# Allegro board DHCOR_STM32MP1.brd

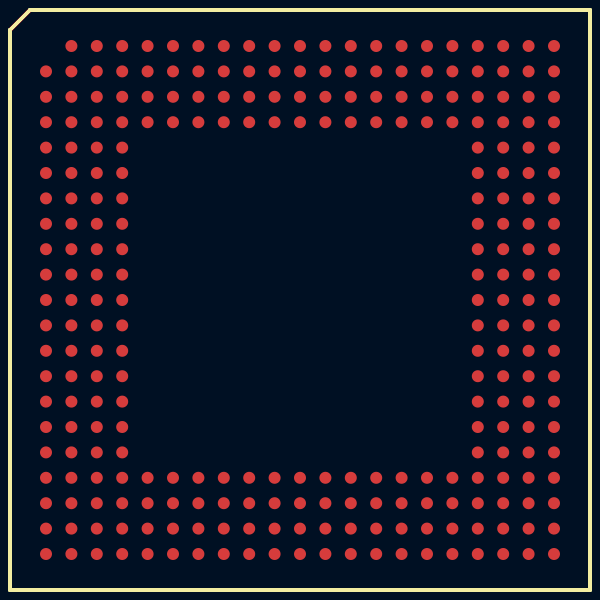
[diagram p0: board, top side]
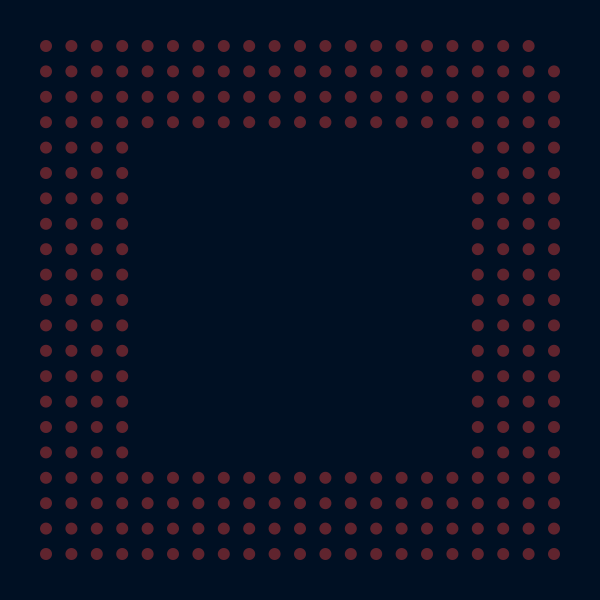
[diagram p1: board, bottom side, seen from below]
No outline. copper layers: TOP, BOTTOM. Coordinates in mm from the lowest, leftmost part position.

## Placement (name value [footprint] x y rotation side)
X?  -  [unnamed]  0 0 0 top

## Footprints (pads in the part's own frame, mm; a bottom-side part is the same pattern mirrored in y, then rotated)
unnamed
  round 0.6 smd: A2(-11.43,12.7) A3(-10.16,12.7) A4(-8.89,12.7) A5(-7.62,12.7) A6(-6.35,12.7) A7(-5.08,12.7) A8(-3.81,12.7) A9(-2.54,12.7) A10(-1.27,12.7) A11(0,12.7) A12(1.27,12.7) A13(2.54,12.7) A14(3.81,12.7) A15(5.08,12.7) A16(6.35,12.7) A17(7.62,12.7) A18(8.89,12.7) A19(10.16,12.7) A20(11.43,12.7) A21(12.7,12.7) AA1(-12.7,-12.7) AA2(-11.43,-12.7) AA3(-10.16,-12.7) AA4(-8.89,-12.7) AA5(-7.62,-12.7) AA6(-6.35,-12.7) AA7(-5.08,-12.7) AA8(-3.81,-12.7) AA9(-2.54,-12.7) AA10(-1.27,-12.7) AA11(0,-12.7) AA12(1.27,-12.7) AA13(2.54,-12.7) AA14(3.81,-12.7) AA15(5.08,-12.7) AA16(6.35,-12.7) AA17(7.62,-12.7) AA18(8.89,-12.7) AA19(10.16,-12.7) AA20(11.43,-12.7) AA21(12.7,-12.7) B1(-12.7,11.43) B2(-11.43,11.43) B3(-10.16,11.43) B4(-8.89,11.43) B5(-7.62,11.43) B6(-6.35,11.43) B7(-5.08,11.43) B8(-3.81,11.43) B9(-2.54,11.43) B10(-1.27,11.43) B11(0,11.43) B12(1.27,11.43) B13(2.54,11.43) B14(3.81,11.43) B15(5.08,11.43) B16(6.35,11.43) B17(7.62,11.43) B18(8.89,11.43) B19(10.16,11.43) B20(11.43,11.43) B21(12.7,11.43) C1(-12.7,10.16) C2(-11.43,10.16) C3(-10.16,10.16) C4(-8.89,10.16) C5(-7.62,10.16) C6(-6.35,10.16) C7(-5.08,10.16) C8(-3.81,10.16) C9(-2.54,10.16) C10(-1.27,10.16) C11(0,10.16) C12(1.27,10.16) C13(2.54,10.16) C14(3.81,10.16) C15(5.08,10.16) C16(6.35,10.16) C17(7.62,10.16) C18(8.89,10.16) C19(10.16,10.16) C20(11.43,10.16) C21(12.7,10.16) D1(-12.7,8.89) D2(-11.43,8.89) D3(-10.16,8.89) D4(-8.89,8.89) D5(-7.62,8.89) D6(-6.35,8.89) D7(-5.08,8.89) D8(-3.81,8.89) D9(-2.54,8.89) D10(-1.27,8.89) D11(0,8.89) D12(1.27,8.89) D13(2.54,8.89) D14(3.81,8.89) D15(5.08,8.89) D16(6.35,8.89) D17(7.62,8.89) D18(8.89,8.89) D19(10.16,8.89) D20(11.43,8.89) D21(12.7,8.89) E1(-12.7,7.62) E2(-11.43,7.62) E3(-10.16,7.62) E4(-8.89,7.62) E18(8.89,7.62) E19(10.16,7.62) E20(11.43,7.62) E21(12.7,7.62) F1(-12.7,6.35) F2(-11.43,6.35) F3(-10.16,6.35) F4(-8.89,6.35) F18(8.89,6.35) F19(10.16,6.35) F20(11.43,6.35) F21(12.7,6.35) G1(-12.7,5.08) G2(-11.43,5.08) G3(-10.16,5.08) G4(-8.89,5.08) G18(8.89,5.08) G19(10.16,5.08) G20(11.43,5.08) G21(12.7,5.08) H1(-12.7,3.81) H2(-11.43,3.81) H3(-10.16,3.81) H4(-8.89,3.81) H18(8.89,3.81) H19(10.16,3.81) H20(11.43,3.81) H21(12.7,3.81) J1(-12.7,2.54) J2(-11.43,2.54) J3(-10.16,2.54) J4(-8.89,2.54) J18(8.89,2.54) J19(10.16,2.54) J20(11.43,2.54) J21(12.7,2.54) K1(-12.7,1.27) K2(-11.43,1.27) K3(-10.16,1.27) K4(-8.89,1.27) K18(8.89,1.27) K19(10.16,1.27) K20(11.43,1.27) K21(12.7,1.27) L1(-12.7,0) L2(-11.43,0) L3(-10.16,0) L4(-8.89,0) L18(8.89,0) L19(10.16,0) L20(11.43,0) L21(12.7,0) M1(-12.7,-1.27) M2(-11.43,-1.27) M3(-10.16,-1.27) M4(-8.89,-1.27) M18(8.89,-1.27) M19(10.16,-1.27) M20(11.43,-1.27) M21(12.7,-1.27) N1(-12.7,-2.54) N2(-11.43,-2.54) N3(-10.16,-2.54) N4(-8.89,-2.54) N18(8.89,-2.54) N19(10.16,-2.54) N20(11.43,-2.54) N21(12.7,-2.54) P1(-12.7,-3.81) P2(-11.43,-3.81) P3(-10.16,-3.81) P4(-8.89,-3.81) P18(8.89,-3.81) P19(10.16,-3.81) P20(11.43,-3.81) P21(12.7,-3.81) R1(-12.7,-5.08) R2(-11.43,-5.08) R3(-10.16,-5.08) R4(-8.89,-5.08) R18(8.89,-5.08) R19(10.16,-5.08) R20(11.43,-5.08) R21(12.7,-5.08) T1(-12.7,-6.35) T2(-11.43,-6.35) T3(-10.16,-6.35) T4(-8.89,-6.35) T18(8.89,-6.35) T19(10.16,-6.35) T20(11.43,-6.35) T21(12.7,-6.35) U1(-12.7,-7.62) U2(-11.43,-7.62) U3(-10.16,-7.62) U4(-8.89,-7.62) U18(8.89,-7.62) U19(10.16,-7.62) U20(11.43,-7.62) U21(12.7,-7.62) V1(-12.7,-8.89) V2(-11.43,-8.89) V3(-10.16,-8.89) V4(-8.89,-8.89) V5(-7.62,-8.89) V6(-6.35,-8.89) V7(-5.08,-8.89) V8(-3.81,-8.89) V9(-2.54,-8.89) V10(-1.27,-8.89) V11(0,-8.89) V12(1.27,-8.89) V13(2.54,-8.89) V14(3.81,-8.89) V15(5.08,-8.89) V16(6.35,-8.89) V17(7.62,-8.89) V18(8.89,-8.89) V19(10.16,-8.89) V20(11.43,-8.89) V21(12.7,-8.89) W1(-12.7,-10.16) W2(-11.43,-10.16) W3(-10.16,-10.16) W4(-8.89,-10.16) W5(-7.62,-10.16) W6(-6.35,-10.16) W7(-5.08,-10.16) W8(-3.81,-10.16) W9(-2.54,-10.16) W10(-1.27,-10.16) W11(0,-10.16) W12(1.27,-10.16) W13(2.54,-10.16) W14(3.81,-10.16) W15(5.08,-10.16) W16(6.35,-10.16) W17(7.62,-10.16) W18(8.89,-10.16) W19(10.16,-10.16) W20(11.43,-10.16) W21(12.7,-10.16) Y1(-12.7,-11.43) Y2(-11.43,-11.43) Y3(-10.16,-11.43) Y4(-8.89,-11.43) Y5(-7.62,-11.43) Y6(-6.35,-11.43) Y7(-5.08,-11.43) Y8(-3.81,-11.43) Y9(-2.54,-11.43) Y10(-1.27,-11.43) Y11(0,-11.43) Y12(1.27,-11.43) Y13(2.54,-11.43) Y14(3.81,-11.43) Y15(5.08,-11.43) Y16(6.35,-11.43) Y17(7.62,-11.43) Y18(8.89,-11.43) Y19(10.16,-11.43) Y20(11.43,-11.43) Y21(12.7,-11.43)

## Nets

Pads without a net: X? A2 A3 A4 A5 A6 A7 A8 A9 A10 A11 A12 A13 A14 A15 A16 A17 A18 A19 A20 A21 AA1 AA2 AA3 AA4 AA5 AA6 AA7 AA8 AA9 AA10 AA11 AA12 AA13 AA14 AA15 AA16 AA17 AA18 AA19 AA20 AA21 B1 B2 B3 B4 B5 B6 B7 B8 B9 B10 B11 B12 B13 B14 B15 B16 B17 B18 B19 B20 B21 C1 C2 C3 C4 C5 C6 C7 C8 C9 C10 C11 C12 C13 C14 C15 C16 C17 C18 C19 C20 C21 D1 D2 D3 D4 D5 D6 D7 D8 D9 D10 D11 D12 D13 D14 D15 D16 D17 D18 D19 D20 D21 E1 E2 E3 E4 E18 E19 E20 E21 F1 F2 F3 F4 F18 F19 F20 F21 G1 G2 G3 G4 G18 G19 G20 G21 H1 H2 H3 H4 H18 H19 H20 H21 J1 J2 J3 J4 J18 J19 J20 J21 K1 K2 K3 K4 K18 K19 K20 K21 L1 L2 L3 L4 L18 L19 L20 L21 M1 M2 M3 M4 M18 M19 M20 M21 N1 N2 N3 N4 N18 N19 N20 N21 P1 P2 P3 P4 P18 P19 P20 P21 R1 R2 R3 R4 R18 R19 R20 R21 T1 T2 T3 T4 T18 T19 T20 T21 U1 U2 U3 U4 U18 U19 U20 U21 V1 V2 V3 V4 V5 V6 V7 V8 V9 V10 V11 V12 V13 V14 V15 V16 V17 V18 V19 V20 V21 W1 W2 W3 W4 W5 W6 W7 W8 W9 W10 W11 W12 W13 W14 W15 W16 W17 W18 W19 W20 W21 Y1 Y2 Y3 Y4 Y5 Y6 Y7 Y8 Y9 Y10 Y11 Y12 Y13 Y14 Y15 Y16 Y17 Y18 Y19 Y20 Y21
